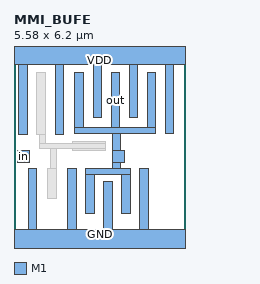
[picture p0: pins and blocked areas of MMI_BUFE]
MACRO MMI_BUFE
	CLASS CORE ;
	FOREIGN MMI_BUFE 0 0 ;
	SIZE 5.58 BY 6.2 ;
	SYMMETRY X Y ;
	SITE CORE1 ;
	PIN out
		DIRECTION output ;
		USE SIGNAL ;
		PORT
			LAYER M1 ;
			RECT 1.99 3.725 2.27 5.52 ;
			LAYER M1 ;
			RECT 3.17 3.725 3.45 5.52 ;
			LAYER M1 ;
			RECT 4.35 3.725 4.63 5.52 ;
			LAYER M1 ;
			RECT 1.99 3.535 4.63 3.725 ;
			LAYER M1 ;
			RECT 1.995 3.53 4.63 3.535 ;
			LAYER M1 ;
			RECT 3.2 2.98 3.485 3.53 ;
			LAYER M1 ;
			RECT 3.2 2.6 3.6 2.98 ;
			LAYER M1 ;
			RECT 3.2 2.4 3.485 2.6 ;
			LAYER M1 ;
			RECT 2.34 2.205 3.8 2.4 ;
			LAYER M1 ;
			RECT 2.34 0.93 2.62 2.205 ;
			LAYER M1 ;
			RECT 3.52 0.93 3.8 2.205 ;
		END
		AntennaDiffArea 4.0678 ;
	END out
	PIN GND
		DIRECTION inout ;
		USE GROUND ;
		PORT
			LAYER M1 ;
			RECT 0.47 0.42 0.75 2.4 ;
			LAYER M1 ;
			RECT 1.75 0.42 2.03 2.4 ;
			LAYER M1 ;
			RECT 2.93 0.42 3.21 1.99 ;
			LAYER M1 ;
			RECT 4.11 0.42 4.39 2.4 ;
			LAYER M1 ;
			RECT 0 -0.42 5.58 0.42 ;
		END
	END GND
	PIN VDD
		DIRECTION inout ;
		USE POWER ;
		PORT
			LAYER M1 ;
			RECT 0 5.78 5.58 6.62 ;
			LAYER M1 ;
			RECT 0.16 3.515 0.44 5.78 ;
			LAYER M1 ;
			RECT 1.34 3.515 1.62 5.78 ;
			LAYER M1 ;
			RECT 2.58 4.065 2.86 5.78 ;
			LAYER M1 ;
			RECT 3.76 4.065 4.04 5.78 ;
			LAYER M1 ;
			RECT 4.94 3.535 5.22 5.78 ;
		END
	END VDD
	PIN in
		DIRECTION input ;
		USE SIGNAL ;
		PORT
			LAYER M1 ;
			RECT 0.12 2.6 0.5 2.98 ;
		END
		AntennaGateArea 0.936 ;
	END in
	OBS
		LAYER M1 ;
		RECT 0.75 3.515 1.03 5.525 ;
		LAYER M1 ;
		RECT 0.835 3.23 1.03 3.515 ;
		LAYER M1 ;
		RECT 1.92 3.23 2.98 3.275 ;
		LAYER M1 ;
		RECT 0.835 3.04 2.98 3.23 ;
		LAYER M1 ;
		RECT 1.19 2.4 1.38 3.04 ;
		LAYER M1 ;
		RECT 1.92 2.995 2.98 3.04 ;
		LAYER M1 ;
		RECT 1.1 1.43 1.38 2.4 ;
	END
END MMI_BUFE
